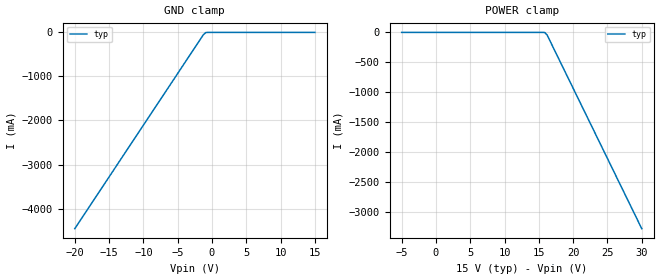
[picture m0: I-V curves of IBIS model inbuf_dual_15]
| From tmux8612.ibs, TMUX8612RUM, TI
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| inbuf_dual_15
[Model]   inbuf_dual_15
Model_type   Input
Vinl = 0.8
Vinh = 1.3
|   typ   min   max
C_comp   6.362683e-13   NA   NA
[Voltage Range]   15   NA   NA
[Temperature Range]   27   NA   NA
[Power Clamp Reference]   15   NA   NA
[GND Clamp Reference]   0   NA   NA
[GND Clamp]
|   Voltage   I(typ)   I(min)   I(max)
-20V      -4.456A    NA         NA
-1.263V   -54.84mA   NA         NA
-909.1mV  -4.166mA   NA         NA
-555.6mV  -13.25uA   NA         NA
15V       922.6nA    NA         NA
[POWER Clamp]
|   Voltage   I(typ)   I(min)   I(max)
-5V       1.235uA    NA         NA
15.15V    -15.77nA   NA         NA
15.51V    -7.895uA   NA         NA
15.86V    -1.962mA   NA         NA
16.21V    -44.85mA   NA         NA
30V       -3.278A    NA         NA
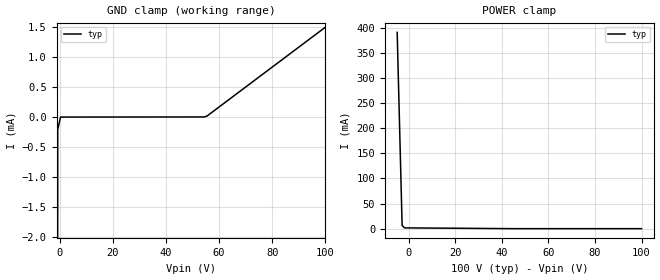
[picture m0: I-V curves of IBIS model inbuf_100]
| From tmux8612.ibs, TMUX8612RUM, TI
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| inbuf_100
[Model]   inbuf_100
Model_type   Input
Vinl = 0.8
Vinh = 1.3
|   typ   min   max
C_comp   1.008417e-12   NA   NA
[Voltage Range]   100   NA   NA
[Temperature Range]   27   NA   NA
[Power Clamp Reference]   100   NA   NA
[GND Clamp Reference]   0   NA   NA
[GND Clamp]
|   Voltage   I(typ)   I(min)   I(max)
-5V       -911.1mA   NA         NA
-1.818V   -174.8mA   NA         NA
-757.6mV  -210.6uA   NA         NA
303mV     30.78nA    NA         NA
54.39V    1.611uA    NA         NA
55.45V    16.74uA    NA         NA
100V      1.498mA    NA         NA
[POWER Clamp]
|   Voltage   I(typ)   I(min)   I(max)
-5V       391.1mA    NA         NA
-2.879V   6.408mA    NA         NA
-1.818V   1.56mA     NA         NA
44.85V    7.951uA    NA         NA
45.91V    1.599uA    NA         NA
100V      -139.8pA   NA         NA
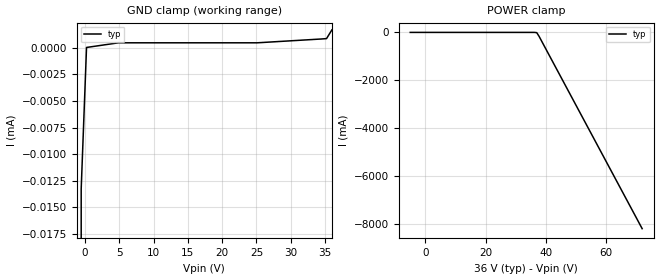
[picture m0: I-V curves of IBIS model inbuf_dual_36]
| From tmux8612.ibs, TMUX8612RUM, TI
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| inbuf_dual_36
[Model]   inbuf_dual_36
Model_type   Input
Vinl = 0.8
Vinh = 1.3
|   typ   min   max
C_comp   1.008417e-12   NA   NA
[Voltage Range]   36   NA   NA
[Temperature Range]   27   NA   NA
[Power Clamp Reference]   36   NA   NA
[GND Clamp Reference]   0   NA   NA
[GND Clamp]
|   Voltage   I(typ)   I(min)   I(max)
-41V      -9.364A    NA         NA
-1.333V   -69.29mA   NA         NA
-555.6mV  -13.25uA   NA         NA
222.2mV   22.54nA    NA         NA
4.889V    458.7nA    NA         NA
25.11V    459.1nA    NA         NA
34.44V    816.4nA    NA         NA
35.22V    852.4nA    NA         NA
36V       1.669uA    NA         NA
[POWER Clamp]
|   Voltage   I(typ)   I(min)   I(max)
-5V       2.074uA    NA         NA
36.22V    -26.64nA   NA         NA
37V       -10.9mA    NA         NA
37.78V    -165.8mA   NA         NA
72V       -8.202A    NA         NA
